VERSION 5.8 ;
BUSBITCHARS "[]" ;
DIVIDERCHAR "/" ;

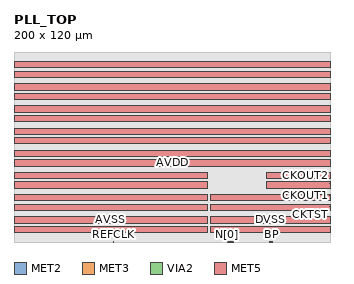
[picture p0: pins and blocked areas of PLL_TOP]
MACRO PLL_TOP
  CLASS BLOCK ;
  ORIGIN 0 0 ;
  FOREIGN PLL_TOP 0 0 ;
  SIZE 200 BY 120 ;
  SYMMETRY X Y R90 ;
  PIN BP
    DIRECTION INPUT ;
    USE SIGNAL ;
    PORT
      LAYER MET2 ;
        RECT 162.705 0 162.915 0.5 ;
      LAYER MET3 ;
        RECT 162.705 0 162.915 0.5 ;
      LAYER VIA2 ;
        RECT 162.765 0.35 162.855 0.44 ;
        RECT 162.765 0.13 162.855 0.22 ;
    END
  END BP
  PIN CKOUT1
    DIRECTION OUTPUT ;
    USE SIGNAL ;
    PORT
      LAYER MET2 ;
        RECT 199.5 29.52 200 29.73 ;
      LAYER MET3 ;
        RECT 199.5 29.52 200 29.73 ;
      LAYER VIA2 ;
        RECT 199.56 29.58 199.65 29.67 ;
        RECT 199.78 29.58 199.87 29.67 ;
    END
  END CKOUT1
  PIN CKOUT2
    DIRECTION OUTPUT ;
    USE SIGNAL ;
    PORT
      LAYER MET2 ;
        RECT 199.5 36.72 200 36.93 ;
      LAYER MET3 ;
        RECT 199.5 36.72 200 36.93 ;
      LAYER VIA2 ;
        RECT 199.56 36.78 199.65 36.87 ;
        RECT 199.78 36.78 199.87 36.87 ;
    END
  END CKOUT2
  PIN CKTST
    DIRECTION OUTPUT ;
    USE SIGNAL ;
    PORT
      LAYER MET2 ;
        RECT 199.5 22.32 200 22.53 ;
      LAYER MET3 ;
        RECT 199.5 22.32 200 22.53 ;
      LAYER VIA2 ;
        RECT 199.56 22.38 199.65 22.47 ;
        RECT 199.78 22.38 199.87 22.47 ;
    END
  END CKTST
  PIN EN
    DIRECTION INPUT ;
    USE SIGNAL ;
    PORT
      LAYER MET2 ;
        RECT 163.215 0 163.425 0.5 ;
      LAYER MET3 ;
        RECT 163.215 0 163.425 0.5 ;
      LAYER VIA2 ;
        RECT 163.275 0.35 163.365 0.44 ;
        RECT 163.275 0.13 163.365 0.22 ;
    END
  END EN
  PIN N[0]
    DIRECTION INPUT ;
    USE SIGNAL ;
    PORT
      LAYER MET2 ;
        RECT 134.555 0 134.765 0.5 ;
      LAYER MET3 ;
        RECT 134.555 0 134.765 0.5 ;
      LAYER VIA2 ;
        RECT 134.615 0.35 134.705 0.44 ;
        RECT 134.615 0.13 134.705 0.22 ;
    END
  END N[0]
  PIN N[1]
    DIRECTION INPUT ;
    USE SIGNAL ;
    PORT
      LAYER MET2 ;
        RECT 135.065 0 135.275 0.5 ;
      LAYER MET3 ;
        RECT 135.065 0 135.275 0.5 ;
      LAYER VIA2 ;
        RECT 135.125 0.35 135.215 0.44 ;
        RECT 135.125 0.13 135.215 0.22 ;
    END
  END N[1]
  PIN N[2]
    DIRECTION INPUT ;
    USE SIGNAL ;
    PORT
      LAYER MET2 ;
        RECT 135.575 0 135.785 0.5 ;
      LAYER MET3 ;
        RECT 135.575 0 135.785 0.5 ;
      LAYER VIA2 ;
        RECT 135.635 0.35 135.725 0.44 ;
        RECT 135.635 0.13 135.725 0.22 ;
    END
  END N[2]
  PIN N[3]
    DIRECTION INPUT ;
    USE SIGNAL ;
    PORT
      LAYER MET2 ;
        RECT 136.085 0 136.295 0.5 ;
      LAYER MET3 ;
        RECT 136.085 0 136.295 0.5 ;
      LAYER VIA2 ;
        RECT 136.145 0.35 136.235 0.44 ;
        RECT 136.145 0.13 136.235 0.22 ;
    END
  END N[3]
  PIN N[4]
    DIRECTION INPUT ;
    USE SIGNAL ;
    PORT
      LAYER MET2 ;
        RECT 136.595 0 136.805 0.5 ;
      LAYER MET3 ;
        RECT 136.595 0 136.805 0.5 ;
      LAYER VIA2 ;
        RECT 136.655 0.35 136.745 0.44 ;
        RECT 136.655 0.13 136.745 0.22 ;
    END
  END N[4]
  PIN N[5]
    DIRECTION INPUT ;
    USE SIGNAL ;
    PORT
      LAYER MET2 ;
        RECT 137.105 0 137.315 0.5 ;
      LAYER MET3 ;
        RECT 137.105 0 137.315 0.5 ;
      LAYER VIA2 ;
        RECT 137.165 0.35 137.255 0.44 ;
        RECT 137.165 0.13 137.255 0.22 ;
    END
  END N[5]
  PIN N[6]
    DIRECTION INPUT ;
    USE SIGNAL ;
    PORT
      LAYER MET2 ;
        RECT 137.615 0 137.825 0.5 ;
      LAYER MET3 ;
        RECT 137.615 0 137.825 0.5 ;
      LAYER VIA2 ;
        RECT 137.675 0.35 137.765 0.44 ;
        RECT 137.675 0.13 137.765 0.22 ;
    END
  END N[6]
  PIN N[7]
    DIRECTION INPUT ;
    USE SIGNAL ;
    PORT
      LAYER MET2 ;
        RECT 138.125 0 138.335 0.5 ;
      LAYER MET3 ;
        RECT 138.125 0 138.335 0.5 ;
      LAYER VIA2 ;
        RECT 138.185 0.35 138.275 0.44 ;
        RECT 138.185 0.13 138.275 0.22 ;
    END
  END N[7]
  PIN OD[0]
    DIRECTION INPUT ;
    USE SIGNAL ;
    PORT
      LAYER MET2 ;
        RECT 161.175 0 161.385 0.5 ;
      LAYER MET3 ;
        RECT 161.175 0 161.385 0.5 ;
      LAYER VIA2 ;
        RECT 161.235 0.35 161.325 0.44 ;
        RECT 161.235 0.13 161.325 0.22 ;
    END
  END OD[0]
  PIN OD[1]
    DIRECTION INPUT ;
    USE SIGNAL ;
    PORT
      LAYER MET2 ;
        RECT 161.685 0 161.895 0.5 ;
      LAYER MET3 ;
        RECT 161.685 0 161.895 0.5 ;
      LAYER VIA2 ;
        RECT 161.745 0.35 161.835 0.44 ;
        RECT 161.745 0.13 161.835 0.22 ;
    END
  END OD[1]
  PIN REFCLK
    DIRECTION INPUT ;
    USE SIGNAL ;
    PORT
      LAYER MET2 ;
        RECT 62.66 0 62.87 0.5 ;
      LAYER MET3 ;
        RECT 62.66 0 62.87 0.5 ;
      LAYER VIA2 ;
        RECT 62.72 0.35 62.81 0.44 ;
        RECT 62.72 0.13 62.81 0.22 ;
    END
  END REFCLK
  PIN SELECT
    DIRECTION INPUT ;
    USE SIGNAL ;
    PORT
      LAYER MET2 ;
        RECT 162.195 0 162.405 0.5 ;
      LAYER MET3 ;
        RECT 162.195 0 162.405 0.5 ;
      LAYER VIA2 ;
        RECT 162.255 0.35 162.345 0.44 ;
        RECT 162.255 0.13 162.345 0.22 ;
    END
  END SELECT
  PIN AVDD
    DIRECTION INOUT ;
    USE POWER ;
    SHAPE ABUTMENT ;
    PORT
      LAYER MET5 ;
        RECT 0 48 200 52 ;
        RECT 0 54 200 58 ;
        RECT 0 62 200 66 ;
        RECT 0 68 200 72 ;
        RECT 0 76 200 80 ;
        RECT 0 82 200 86 ;
        RECT 0 90 200 94 ;
        RECT 0 96 200 100 ;
        RECT 0 104 200 108 ;
        RECT 0 110 200 114 ;
        RECT 0 6 122.18 10 ;
        RECT 0 20 122.18 24 ;
        RECT 0 34 122.18 38 ;
    END
  END AVDD
  PIN AVSS
    DIRECTION INOUT ;
    USE GROUND ;
    SHAPE ABUTMENT ;
    PORT
      LAYER MET5 ;
        RECT 0 12 122.18 16 ;
        RECT 0 26 122.18 30 ;
        RECT 0 40 122.18 44 ;
    END
  END AVSS
  PIN DVDD
    DIRECTION INOUT ;
    USE POWER ;
    PORT
      LAYER MET5 ;
        RECT 123.925 6 200 10 ;
        RECT 123.925 20 200 24 ;
    END
  END DVDD
  PIN DVDD_DRV
    DIRECTION INOUT ;
    USE POWER ;
    PORT
      LAYER MET5 ;
        RECT 159.52 34 200 38 ;
    END
  END DVDD_DRV
  PIN DVSS
    DIRECTION INOUT ;
    USE GROUND ;
    PORT
      LAYER MET5 ;
        RECT 123.925 12 200 16 ;
        RECT 123.925 26 200 30 ;
    END
  END DVSS
  PIN DVSS_DRV
    DIRECTION INOUT ;
    USE GROUND ;
    PORT
      LAYER MET5 ;
        RECT 159.52 40 200 44 ;
    END
  END DVSS_DRV
  OBS
    LAYER MET1 SPACING 0.09 ;
      RECT 0 0 200 120 ;
    LAYER MET2 SPACING 0.1 ;
      RECT 0 37.105 200 120 ;
      RECT 0 0.675 199.325 120 ;
      RECT 0 29.905 200 36.545 ;
      RECT 0 22.705 200 29.345 ;
      RECT 163.6 0 200 22.145 ;
      RECT 138.51 0 161 120 ;
      RECT 63.045 0 134.38 120 ;
      RECT 0 0 62.485 120 ;
    LAYER MET3 SPACING 0.1 ;
      RECT 0 37.105 200 120 ;
      RECT 0 0.675 199.325 120 ;
      RECT 0 29.905 200 36.545 ;
      RECT 0 22.705 200 29.345 ;
      RECT 163.6 0 200 22.145 ;
      RECT 138.51 0 161 120 ;
      RECT 63.045 0 134.38 120 ;
      RECT 0 0 62.485 120 ;
    LAYER MET4 SPACING 0.1 ;
      RECT 0 37.095 200 120 ;
      RECT 0 0.665 199.335 120 ;
      RECT 0 29.895 200 36.555 ;
      RECT 0 22.695 200 29.355 ;
      RECT 163.59 0 200 22.155 ;
      RECT 138.5 0 161.01 120 ;
      RECT 63.035 0 134.39 120 ;
      RECT 0 0 62.495 120 ;
    LAYER MET5 SPACING 0.1 ;
      RECT 0 44.33 200 47.67 ;
      RECT 122.51 30.33 159.19 47.67 ;
      RECT 0 38.33 200 39.67 ;
      RECT 0 30.33 200 33.67 ;
      RECT 122.51 0 123.595 47.67 ;
      RECT 0 24.33 200 25.67 ;
      RECT 0 16.33 200 19.67 ;
      RECT 0 10.33 200 11.67 ;
      RECT 0 0 200 5.67 ;
      RECT 0 52.33 200 53.67 ;
      RECT 0 58.33 200 61.67 ;
      RECT 0 66.33 200 67.67 ;
      RECT 0 72.33 200 75.67 ;
      RECT 0 80.33 200 81.67 ;
      RECT 0 86.33 200 89.67 ;
      RECT 0 94.33 200 95.67 ;
      RECT 0 100.33 200 103.67 ;
      RECT 0 108.33 200 109.67 ;
      RECT 0 114.33 200 120 ;
    LAYER VIA1 SPACING 0.11 ;
      RECT 0 0 200 120 ;
    LAYER VIA2 SPACING 0.11 ;
      RECT 0 0 200 120 ;
    LAYER VIA3 SPACING 0.11 ;
      RECT 0 0 200 120 ;
    LAYER VIA4 SPACING 0.11 ;
      RECT 0 0 200 120 ;
    LAYER T4M2 SPACING 0.4 ;
      RECT 0 44.6 200 47.4 ;
      RECT 122.78 30.6 158.92 47.4 ;
      RECT 0 38.6 200 39.4 ;
      RECT 0 30.6 200 33.4 ;
      RECT 122.78 0 123.325 47.4 ;
      RECT 0 24.6 200 25.4 ;
      RECT 0 16.6 200 19.4 ;
      RECT 0 10.6 200 11.4 ;
      RECT 0 0 200 5.4 ;
      RECT 0 52.6 200 53.4 ;
      RECT 0 58.6 200 61.4 ;
      RECT 0 66.6 200 67.4 ;
      RECT 0 72.6 200 75.4 ;
      RECT 0 80.6 200 81.4 ;
      RECT 0 86.6 200 89.4 ;
      RECT 0 94.6 200 95.4 ;
      RECT 0 100.6 200 103.4 ;
      RECT 0 108.6 200 109.4 ;
      RECT 0 114.6 200 120 ;
    LAYER T4V2 SPACING 0.34 ;
      RECT 0 0 200 120 ;
    LAYER RV SPACING 3 ;
      RECT 0 0 200 120 ;
    LAYER RDL SPACING 2 ;
      RECT 0 0 200 120 ;
  END
END PLL_TOP

END LIBRARY
